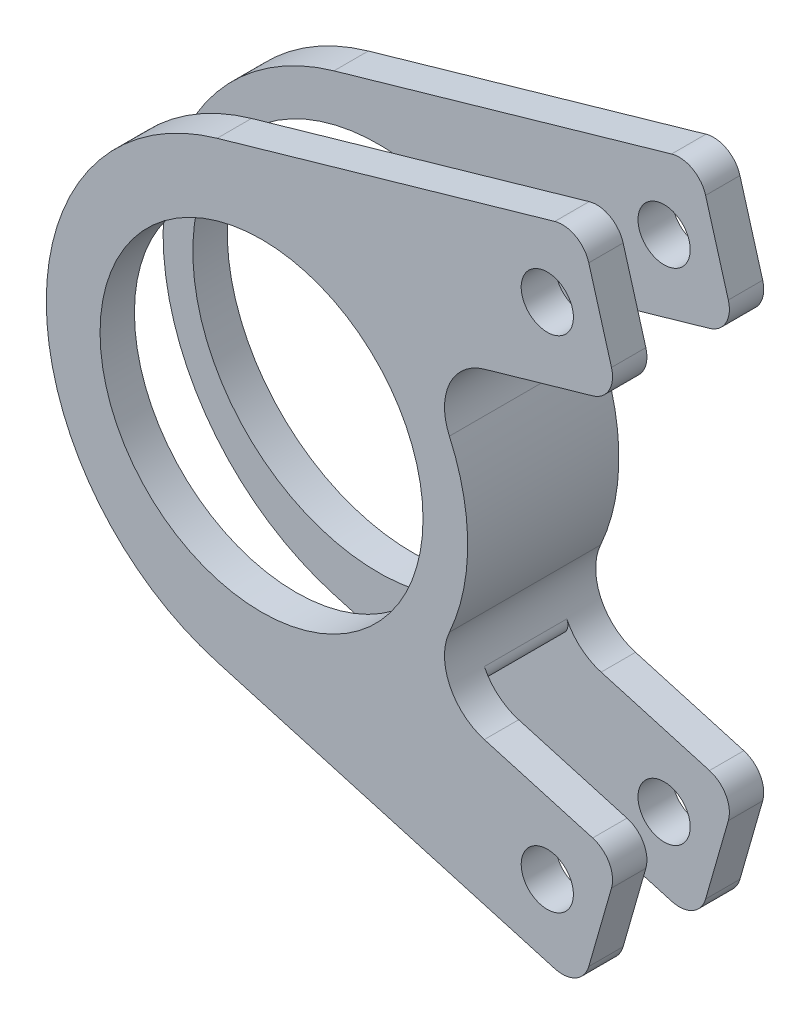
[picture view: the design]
ISO-10303-21;
HEADER;
FILE_DESCRIPTION(('STEP AP214'),'2;1');
FILE_NAME('part.step','',(''),(''),'','','');
FILE_SCHEMA(('AUTOMOTIVE_DESIGN { 1 0 10303 214 1 1 1 1 }'));
ENDSEC;
DATA;
#1=APPLICATION_CONTEXT('core data for automotive mechanical design processes');
#2=APPLICATION_PROTOCOL_DEFINITION('international standard','automotive_design',2000,#1);
#3=PRODUCT_CONTEXT('',#1,'mechanical');
#4=PRODUCT('Part','Part','',(#3));
#5=PRODUCT_RELATED_PRODUCT_CATEGORY('part','',(#4));
#6=PRODUCT_DEFINITION_FORMATION('','',#4);
#7=PRODUCT_DEFINITION_CONTEXT('part definition',#1,'design');
#8=PRODUCT_DEFINITION('design','',#6,#7);
#9=PRODUCT_DEFINITION_SHAPE('','',#8);
#10=(LENGTH_UNIT() NAMED_UNIT(*) SI_UNIT(.MILLI.,.METRE.));
#11=(NAMED_UNIT(*) PLANE_ANGLE_UNIT() SI_UNIT($,.RADIAN.));
#12=(NAMED_UNIT(*) SI_UNIT($,.STERADIAN.) SOLID_ANGLE_UNIT());
#13=UNCERTAINTY_MEASURE_WITH_UNIT(LENGTH_MEASURE(1.E-05),#10,'distance_accuracy_value','');
#14=(GEOMETRIC_REPRESENTATION_CONTEXT(3) GLOBAL_UNCERTAINTY_ASSIGNED_CONTEXT((#13)) GLOBAL_UNIT_ASSIGNED_CONTEXT((#10,
#11,#12)) REPRESENTATION_CONTEXT('',''));
#15=CARTESIAN_POINT('',(0.,0.,0.));
#16=DIRECTION('',(0.,0.,1.));
#17=DIRECTION('',(1.,0.,0.));
#18=AXIS2_PLACEMENT_3D('',#15,#16,#17);
#19=CARTESIAN_POINT('',(658.968984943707,116.70480409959,55.));
#20=DIRECTION('',(-0.275637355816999,0.961261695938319,0.));
#21=DIRECTION('',(-0.961261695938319,-0.275637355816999,0.));
#22=AXIS2_PLACEMENT_3D('',#19,#20,#21);
#23=PLANE('',#22);
#24=DIRECTION('',(0.961261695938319,0.275637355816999,0.));
#25=VECTOR('',#24,1.);
#26=CARTESIAN_POINT('',(849.712684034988,171.399679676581,-30.));
#27=LINE('',#26,#25);
#28=CARTESIAN_POINT('',(658.968984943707,116.70480409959,-30.));
#29=VERTEX_POINT('',#28);
#30=CARTESIAN_POINT('',(737.793083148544,139.307250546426,-30.));
#31=VERTEX_POINT('',#30);
#32=EDGE_CURVE('E280',#29,#31,#27,.T.);
#33=ORIENTED_EDGE('',*,*,#32,.F.);
#34=DIRECTION('',(0.,0.,-1.));
#35=VECTOR('',#34,1.);
#36=CARTESIAN_POINT('',(658.968984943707,116.70480409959,55.));
#37=LINE('',#36,#35);
#38=CARTESIAN_POINT('',(658.968984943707,116.70480409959,-55.));
#39=VERTEX_POINT('',#38);
#40=EDGE_CURVE('E491',#29,#39,#37,.T.);
#41=ORIENTED_EDGE('',*,*,#40,.T.);
#42=DIRECTION('',(0.961261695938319,0.275637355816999,0.));
#43=VECTOR('',#42,1.);
#44=CARTESIAN_POINT('',(658.968984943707,116.70480409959,-55.));
#45=LINE('',#44,#43);
#46=CARTESIAN_POINT('',(737.793083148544,139.307250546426,-55.));
#47=VERTEX_POINT('',#46);
#48=EDGE_CURVE('E417',#39,#47,#45,.T.);
#49=ORIENTED_EDGE('',*,*,#48,.T.);
#50=DIRECTION('',(0.,0.,-1.));
#51=VECTOR('',#50,1.);
#52=CARTESIAN_POINT('',(737.793083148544,139.307250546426,55.));
#53=LINE('',#52,#51);
#54=EDGE_CURVE('E487',#31,#47,#53,.T.);
#55=ORIENTED_EDGE('',*,*,#54,.F.);
#56=EDGE_LOOP('',(#33,#41,#49,#55));
#57=FACE_BOUND('',#56,.T.);
#58=ADVANCED_FACE('F34',(#57),#23,.F.);
#59=CARTESIAN_POINT('',(732.280336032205,158.532484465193,55.));
#60=DIRECTION('',(0.,0.,-1.));
#61=DIRECTION('',(-1.,0.,0.));
#62=AXIS2_PLACEMENT_3D('',#59,#60,#61);
#63=CYLINDRICAL_SURFACE('',#62,20.);
#64=CARTESIAN_POINT('',(732.280336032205,158.532484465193,-30.));
#65=DIRECTION('',(0.,0.,1.));
#66=DIRECTION('',(1.,0.,0.));
#67=AXIS2_PLACEMENT_3D('',#64,#65,#66);
#68=CIRCLE('',#67,20.);
#69=CARTESIAN_POINT('',(751.505569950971,164.045231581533,-30.));
#70=VERTEX_POINT('',#69);
#71=EDGE_CURVE('E361',#31,#70,#68,.T.);
#72=ORIENTED_EDGE('',*,*,#71,.F.);
#73=ORIENTED_EDGE('',*,*,#54,.T.);
#74=CARTESIAN_POINT('',(732.280336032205,158.532484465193,-55.));
#75=DIRECTION('',(0.,0.,1.));
#76=DIRECTION('',(1.,0.,0.));
#77=AXIS2_PLACEMENT_3D('',#74,#75,#76);
#78=CIRCLE('',#77,20.);
#79=CARTESIAN_POINT('',(751.505569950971,164.045231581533,-55.));
#80=VERTEX_POINT('',#79);
#81=EDGE_CURVE('E420',#47,#80,#78,.T.);
#82=ORIENTED_EDGE('',*,*,#81,.T.);
#83=DIRECTION('',(0.,0.,-1.));
#84=VECTOR('',#83,1.);
#85=CARTESIAN_POINT('',(751.505569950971,164.045231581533,55.));
#86=LINE('',#85,#84);
#87=EDGE_CURVE('E483',#70,#80,#86,.T.);
#88=ORIENTED_EDGE('',*,*,#87,.F.);
#89=EDGE_LOOP('',(#72,#73,#82,#88));
#90=FACE_BOUND('',#89,.T.);
#91=ADVANCED_FACE('F611',(#90),#63,.T.);
#92=CARTESIAN_POINT('',(751.505569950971,164.045231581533,55.));
#93=DIRECTION('',(-0.961261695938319,-0.275637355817,0.));
#94=DIRECTION('',(0.275637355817,-0.961261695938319,0.));
#95=AXIS2_PLACEMENT_3D('',#92,#93,#94);
#96=PLANE('',#95);
#97=DIRECTION('',(-0.275637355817,0.961261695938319,0.));
#98=VECTOR('',#97,1.);
#99=CARTESIAN_POINT('',(751.505569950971,164.045231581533,-30.));
#100=LINE('',#99,#98);
#101=CARTESIAN_POINT('',(734.967328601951,221.720933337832,-30.));
#102=VERTEX_POINT('',#101);
#103=EDGE_CURVE('E359',#70,#102,#100,.T.);
#104=ORIENTED_EDGE('',*,*,#103,.F.);
#105=ORIENTED_EDGE('',*,*,#87,.T.);
#106=DIRECTION('',(-0.275637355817,0.961261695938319,0.));
#107=VECTOR('',#106,1.);
#108=CARTESIAN_POINT('',(751.505569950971,164.045231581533,-55.));
#109=LINE('',#108,#107);
#110=CARTESIAN_POINT('',(734.967328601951,221.720933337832,-55.));
#111=VERTEX_POINT('',#110);
#112=EDGE_CURVE('E423',#80,#111,#109,.T.);
#113=ORIENTED_EDGE('',*,*,#112,.T.);
#114=DIRECTION('',(0.,0.,-1.));
#115=VECTOR('',#114,1.);
#116=CARTESIAN_POINT('',(734.967328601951,221.720933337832,55.));
#117=LINE('',#116,#115);
#118=EDGE_CURVE('E479',#102,#111,#117,.T.);
#119=ORIENTED_EDGE('',*,*,#118,.F.);
#120=EDGE_LOOP('',(#104,#105,#113,#119));
#121=FACE_BOUND('',#120,.T.);
#122=ADVANCED_FACE('F617',(#121),#96,.F.);
#123=CARTESIAN_POINT('',(715.742094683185,216.208186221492,55.));
#124=DIRECTION('',(0.,0.,-1.));
#125=DIRECTION('',(-1.,0.,0.));
#126=AXIS2_PLACEMENT_3D('',#123,#124,#125);
#127=CYLINDRICAL_SURFACE('',#126,20.);
#128=CARTESIAN_POINT('',(715.742094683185,216.208186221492,-30.));
#129=DIRECTION('',(0.,0.,1.));
#130=DIRECTION('',(1.,0.,0.));
#131=AXIS2_PLACEMENT_3D('',#128,#129,#130);
#132=CIRCLE('',#131,20.);
#133=CARTESIAN_POINT('',(710.229347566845,235.433420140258,-30.));
#134=VERTEX_POINT('',#133);
#135=EDGE_CURVE('E357',#102,#134,#132,.T.);
#136=ORIENTED_EDGE('',*,*,#135,.F.);
#137=ORIENTED_EDGE('',*,*,#118,.T.);
#138=CARTESIAN_POINT('',(715.742094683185,216.208186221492,-55.));
#139=DIRECTION('',(0.,0.,1.));
#140=DIRECTION('',(1.,0.,0.));
#141=AXIS2_PLACEMENT_3D('',#138,#139,#140);
#142=CIRCLE('',#141,20.);
#143=CARTESIAN_POINT('',(710.229347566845,235.433420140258,-55.));
#144=VERTEX_POINT('',#143);
#145=EDGE_CURVE('E426',#111,#144,#142,.T.);
#146=ORIENTED_EDGE('',*,*,#145,.T.);
#147=DIRECTION('',(0.,0.,-1.));
#148=VECTOR('',#147,1.);
#149=CARTESIAN_POINT('',(710.229347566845,235.433420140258,55.));
#150=LINE('',#149,#148);
#151=EDGE_CURVE('E475',#134,#144,#150,.T.);
#152=ORIENTED_EDGE('',*,*,#151,.F.);
#153=EDGE_LOOP('',(#136,#137,#146,#152));
#154=FACE_BOUND('',#153,.T.);
#155=ADVANCED_FACE('F676',(#154),#127,.T.);
#156=CARTESIAN_POINT('',(464.549050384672,164.985728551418,55.));
#157=DIRECTION('',(0.275637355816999,-0.961261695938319,0.));
#158=DIRECTION('',(0.961261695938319,0.275637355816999,0.));
#159=AXIS2_PLACEMENT_3D('',#156,#157,#158);
#160=PLANE('',#159);
#161=DIRECTION('',(-0.961261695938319,-0.275637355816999,0.));
#162=VECTOR('',#161,1.);
#163=CARTESIAN_POINT('',(464.549050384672,164.985728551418,-30.));
#164=LINE('',#163,#162);
#165=CARTESIAN_POINT('',(464.549050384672,164.985728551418,-30.));
#166=VERTEX_POINT('',#165);
#167=EDGE_CURVE('E355',#134,#166,#164,.T.);
#168=ORIENTED_EDGE('',*,*,#167,.F.);
#169=ORIENTED_EDGE('',*,*,#151,.T.);
#170=DIRECTION('',(-0.961261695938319,-0.275637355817,0.));
#171=VECTOR('',#170,1.);
#172=CARTESIAN_POINT('',(464.549050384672,164.985728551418,-55.));
#173=LINE('',#172,#171);
#174=CARTESIAN_POINT('',(464.549050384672,164.985728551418,-55.));
#175=VERTEX_POINT('',#174);
#176=EDGE_CURVE('E429',#144,#175,#173,.T.);
#177=ORIENTED_EDGE('',*,*,#176,.T.);
#178=DIRECTION('',(0.,0.,-1.));
#179=VECTOR('',#178,1.);
#180=CARTESIAN_POINT('',(464.549050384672,164.985728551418,55.));
#181=LINE('',#180,#179);
#182=EDGE_CURVE('E471',#166,#175,#181,.T.);
#183=ORIENTED_EDGE('',*,*,#182,.F.);
#184=EDGE_LOOP('',(#168,#169,#177,#183));
#185=FACE_BOUND('',#184,.T.);
#186=ADVANCED_FACE('F673',(#185),#160,.F.);
#187=CARTESIAN_POINT('',(511.857946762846,0.,55.));
#188=DIRECTION('',(0.,0.,-1.));
#189=DIRECTION('',(-1.,0.,0.));
#190=AXIS2_PLACEMENT_3D('',#187,#188,#189);
#191=CYLINDRICAL_SURFACE('',#190,171.634560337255);
#192=CARTESIAN_POINT('',(511.857946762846,0.,-30.));
#193=DIRECTION('',(0.,0.,1.));
#194=DIRECTION('',(1.,0.,0.));
#195=AXIS2_PLACEMENT_3D('',#192,#193,#194);
#196=CIRCLE('',#195,171.634560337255);
#197=CARTESIAN_POINT('',(464.549050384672,-164.985728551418,-30.));
#198=VERTEX_POINT('',#197);
#199=EDGE_CURVE('E353',#166,#198,#196,.T.);
#200=ORIENTED_EDGE('',*,*,#199,.F.);
#201=ORIENTED_EDGE('',*,*,#182,.T.);
#202=CARTESIAN_POINT('',(511.857946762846,0.,-55.));
#203=DIRECTION('',(0.,0.,1.));
#204=DIRECTION('',(1.,0.,0.));
#205=AXIS2_PLACEMENT_3D('',#202,#203,#204);
#206=CIRCLE('',#205,171.634560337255);
#207=CARTESIAN_POINT('',(464.549050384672,-164.985728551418,-55.));
#208=VERTEX_POINT('',#207);
#209=EDGE_CURVE('E432',#175,#208,#206,.T.);
#210=ORIENTED_EDGE('',*,*,#209,.T.);
#211=DIRECTION('',(0.,0.,-1.));
#212=VECTOR('',#211,1.);
#213=CARTESIAN_POINT('',(464.549050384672,-164.985728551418,55.));
#214=LINE('',#213,#212);
#215=EDGE_CURVE('E467',#198,#208,#214,.T.);
#216=ORIENTED_EDGE('',*,*,#215,.F.);
#217=EDGE_LOOP('',(#200,#201,#210,#216));
#218=FACE_BOUND('',#217,.T.);
#219=ADVANCED_FACE('F670',(#218),#191,.T.);
#220=CARTESIAN_POINT('',(464.549050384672,-164.985728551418,55.));
#221=DIRECTION('',(0.275637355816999,0.961261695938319,0.));
#222=DIRECTION('',(-0.961261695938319,0.275637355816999,0.));
#223=AXIS2_PLACEMENT_3D('',#220,#221,#222);
#224=PLANE('',#223);
#225=DIRECTION('',(0.961261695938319,-0.275637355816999,0.));
#226=VECTOR('',#225,1.);
#227=CARTESIAN_POINT('',(464.549050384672,-164.985728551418,-30.));
#228=LINE('',#227,#226);
#229=CARTESIAN_POINT('',(710.229347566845,-235.433420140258,-30.));
#230=VERTEX_POINT('',#229);
#231=EDGE_CURVE('E351',#198,#230,#228,.T.);
#232=ORIENTED_EDGE('',*,*,#231,.F.);
#233=ORIENTED_EDGE('',*,*,#215,.T.);
#234=DIRECTION('',(0.961261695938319,-0.275637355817,0.));
#235=VECTOR('',#234,1.);
#236=CARTESIAN_POINT('',(464.549050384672,-164.985728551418,-55.));
#237=LINE('',#236,#235);
#238=CARTESIAN_POINT('',(710.229347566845,-235.433420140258,-55.));
#239=VERTEX_POINT('',#238);
#240=EDGE_CURVE('E435',#208,#239,#237,.T.);
#241=ORIENTED_EDGE('',*,*,#240,.T.);
#242=DIRECTION('',(0.,0.,-1.));
#243=VECTOR('',#242,1.);
#244=CARTESIAN_POINT('',(710.229347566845,-235.433420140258,55.));
#245=LINE('',#244,#243);
#246=EDGE_CURVE('E463',#230,#239,#245,.T.);
#247=ORIENTED_EDGE('',*,*,#246,.F.);
#248=EDGE_LOOP('',(#232,#233,#241,#247));
#249=FACE_BOUND('',#248,.T.);
#250=ADVANCED_FACE('F667',(#249),#224,.F.);
#251=CARTESIAN_POINT('',(715.742094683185,-216.208186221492,55.));
#252=DIRECTION('',(0.,0.,-1.));
#253=DIRECTION('',(-1.,0.,0.));
#254=AXIS2_PLACEMENT_3D('',#251,#252,#253);
#255=CYLINDRICAL_SURFACE('',#254,20.);
#256=CARTESIAN_POINT('',(715.742094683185,-216.208186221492,-30.));
#257=DIRECTION('',(0.,0.,1.));
#258=DIRECTION('',(1.,0.,0.));
#259=AXIS2_PLACEMENT_3D('',#256,#257,#258);
#260=CIRCLE('',#259,20.);
#261=CARTESIAN_POINT('',(734.967328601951,-221.720933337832,-30.));
#262=VERTEX_POINT('',#261);
#263=EDGE_CURVE('E349',#230,#262,#260,.T.);
#264=ORIENTED_EDGE('',*,*,#263,.F.);
#265=ORIENTED_EDGE('',*,*,#246,.T.);
#266=CARTESIAN_POINT('',(715.742094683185,-216.208186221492,-55.));
#267=DIRECTION('',(0.,0.,1.));
#268=DIRECTION('',(-1.,0.,0.));
#269=AXIS2_PLACEMENT_3D('',#266,#267,#268);
#270=CIRCLE('',#269,20.);
#271=CARTESIAN_POINT('',(734.967328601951,-221.720933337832,-55.));
#272=VERTEX_POINT('',#271);
#273=EDGE_CURVE('E438',#239,#272,#270,.T.);
#274=ORIENTED_EDGE('',*,*,#273,.T.);
#275=DIRECTION('',(0.,0.,-1.));
#276=VECTOR('',#275,1.);
#277=CARTESIAN_POINT('',(734.967328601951,-221.720933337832,55.));
#278=LINE('',#277,#276);
#279=EDGE_CURVE('E459',#262,#272,#278,.T.);
#280=ORIENTED_EDGE('',*,*,#279,.F.);
#281=EDGE_LOOP('',(#264,#265,#274,#280));
#282=FACE_BOUND('',#281,.T.);
#283=ADVANCED_FACE('F664',(#282),#255,.T.);
#284=CARTESIAN_POINT('',(751.505569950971,-164.045231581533,55.));
#285=DIRECTION('',(-0.961261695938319,0.275637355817,0.));
#286=DIRECTION('',(-0.275637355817,-0.961261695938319,0.));
#287=AXIS2_PLACEMENT_3D('',#284,#285,#286);
#288=PLANE('',#287);
#289=DIRECTION('',(0.275637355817,0.961261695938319,0.));
#290=VECTOR('',#289,1.);
#291=CARTESIAN_POINT('',(751.505569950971,-164.045231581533,-30.));
#292=LINE('',#291,#290);
#293=CARTESIAN_POINT('',(751.505569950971,-164.045231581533,-30.));
#294=VERTEX_POINT('',#293);
#295=EDGE_CURVE('E347',#262,#294,#292,.T.);
#296=ORIENTED_EDGE('',*,*,#295,.F.);
#297=ORIENTED_EDGE('',*,*,#279,.T.);
#298=DIRECTION('',(0.275637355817,0.961261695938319,0.));
#299=VECTOR('',#298,1.);
#300=CARTESIAN_POINT('',(751.505569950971,-164.045231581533,-55.));
#301=LINE('',#300,#299);
#302=CARTESIAN_POINT('',(751.505569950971,-164.045231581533,-55.));
#303=VERTEX_POINT('',#302);
#304=EDGE_CURVE('E441',#272,#303,#301,.T.);
#305=ORIENTED_EDGE('',*,*,#304,.T.);
#306=DIRECTION('',(0.,0.,-1.));
#307=VECTOR('',#306,1.);
#308=CARTESIAN_POINT('',(751.505569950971,-164.045231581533,55.));
#309=LINE('',#308,#307);
#310=EDGE_CURVE('E455',#294,#303,#309,.T.);
#311=ORIENTED_EDGE('',*,*,#310,.F.);
#312=EDGE_LOOP('',(#296,#297,#305,#311));
#313=FACE_BOUND('',#312,.T.);
#314=ADVANCED_FACE('F661',(#313),#288,.F.);
#315=CARTESIAN_POINT('',(732.280336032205,-158.532484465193,55.));
#316=DIRECTION('',(0.,0.,-1.));
#317=DIRECTION('',(-1.,0.,0.));
#318=AXIS2_PLACEMENT_3D('',#315,#316,#317);
#319=CYLINDRICAL_SURFACE('',#318,20.);
#320=CARTESIAN_POINT('',(732.280336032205,-158.532484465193,-30.));
#321=DIRECTION('',(0.,0.,1.));
#322=DIRECTION('',(1.,0.,0.));
#323=AXIS2_PLACEMENT_3D('',#320,#321,#322);
#324=CIRCLE('',#323,20.);
#325=CARTESIAN_POINT('',(737.793083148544,-139.307250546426,-30.));
#326=VERTEX_POINT('',#325);
#327=EDGE_CURVE('E345',#294,#326,#324,.T.);
#328=ORIENTED_EDGE('',*,*,#327,.F.);
#329=ORIENTED_EDGE('',*,*,#310,.T.);
#330=CARTESIAN_POINT('',(732.280336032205,-158.532484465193,-55.));
#331=DIRECTION('',(0.,0.,1.));
#332=DIRECTION('',(-1.,0.,0.));
#333=AXIS2_PLACEMENT_3D('',#330,#331,#332);
#334=CIRCLE('',#333,20.);
#335=CARTESIAN_POINT('',(737.793083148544,-139.307250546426,-55.));
#336=VERTEX_POINT('',#335);
#337=EDGE_CURVE('E444',#303,#336,#334,.T.);
#338=ORIENTED_EDGE('',*,*,#337,.T.);
#339=DIRECTION('',(0.,0.,-1.));
#340=VECTOR('',#339,1.);
#341=CARTESIAN_POINT('',(737.793083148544,-139.307250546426,55.));
#342=LINE('',#341,#340);
#343=EDGE_CURVE('E451',#326,#336,#342,.T.);
#344=ORIENTED_EDGE('',*,*,#343,.F.);
#345=EDGE_LOOP('',(#328,#329,#338,#344));
#346=FACE_BOUND('',#345,.T.);
#347=ADVANCED_FACE('F658',(#346),#319,.T.);
#348=CARTESIAN_POINT('',(658.968984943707,-116.70480409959,55.));
#349=DIRECTION('',(-0.275637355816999,-0.961261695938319,0.));
#350=DIRECTION('',(0.961261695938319,-0.275637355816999,0.));
#351=AXIS2_PLACEMENT_3D('',#348,#349,#350);
#352=PLANE('',#351);
#353=DIRECTION('',(-0.961261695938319,0.275637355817,0.));
#354=VECTOR('',#353,1.);
#355=CARTESIAN_POINT('',(860.229370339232,-174.415290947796,-30.));
#356=LINE('',#355,#354);
#357=CARTESIAN_POINT('',(658.968984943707,-116.70480409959,-30.));
#358=VERTEX_POINT('',#357);
#359=EDGE_CURVE('E284',#326,#358,#356,.T.);
#360=ORIENTED_EDGE('',*,*,#359,.F.);
#361=ORIENTED_EDGE('',*,*,#343,.T.);
#362=DIRECTION('',(-0.961261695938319,0.275637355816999,0.));
#363=VECTOR('',#362,1.);
#364=CARTESIAN_POINT('',(658.968984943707,-116.70480409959,-55.));
#365=LINE('',#364,#363);
#366=CARTESIAN_POINT('',(658.968984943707,-116.70480409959,-55.));
#367=VERTEX_POINT('',#366);
#368=EDGE_CURVE('E383',#336,#367,#365,.T.);
#369=ORIENTED_EDGE('',*,*,#368,.T.);
#370=DIRECTION('',(0.,0.,-1.));
#371=VECTOR('',#370,1.);
#372=CARTESIAN_POINT('',(658.968984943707,-116.70480409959,55.));
#373=LINE('',#372,#371);
#374=EDGE_CURVE('E409',#358,#367,#373,.T.);
#375=ORIENTED_EDGE('',*,*,#374,.F.);
#376=EDGE_LOOP('',(#360,#361,#369,#375));
#377=FACE_BOUND('',#376,.T.);
#378=ADVANCED_FACE('F655',(#377),#352,.F.);
#379=CARTESIAN_POINT('',(704.785981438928,181.857588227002,55.));
#380=DIRECTION('',(0.,0.,-1.));
#381=DIRECTION('',(-1.,0.,0.));
#382=AXIS2_PLACEMENT_3D('',#379,#380,#381);
#383=CYLINDRICAL_SURFACE('',#382,19.);
#384=CARTESIAN_POINT('',(704.785981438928,181.857588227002,-55.));
#385=DIRECTION('',(0.,0.,1.));
#386=DIRECTION('',(1.,0.,0.));
#387=AXIS2_PLACEMENT_3D('',#384,#385,#386);
#388=CIRCLE('',#387,19.);
#389=CARTESIAN_POINT('',(723.785981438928,181.857588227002,-55.));
#390=VERTEX_POINT('',#389);
#391=EDGE_CURVE('E367',#390,#390,#388,.T.);
#392=ORIENTED_EDGE('',*,*,#391,.F.);
#393=EDGE_LOOP('',(#392));
#394=FACE_BOUND('',#393,.T.);
#395=CARTESIAN_POINT('',(704.785981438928,181.857588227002,-30.));
#396=DIRECTION('',(0.,0.,1.));
#397=DIRECTION('',(1.,0.,0.));
#398=AXIS2_PLACEMENT_3D('',#395,#396,#397);
#399=CIRCLE('',#398,19.);
#400=CARTESIAN_POINT('',(723.785981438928,181.857588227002,-30.));
#401=VERTEX_POINT('',#400);
#402=EDGE_CURVE('E342',#401,#401,#399,.T.);
#403=ORIENTED_EDGE('',*,*,#402,.T.);
#404=EDGE_LOOP('',(#403));
#405=FACE_BOUND('',#404,.T.);
#406=ADVANCED_FACE('F751',(#394,#405),#383,.F.);
#407=CARTESIAN_POINT('',(704.785981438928,-181.857588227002,55.));
#408=DIRECTION('',(0.,0.,-1.));
#409=DIRECTION('',(-1.,0.,0.));
#410=AXIS2_PLACEMENT_3D('',#407,#408,#409);
#411=CYLINDRICAL_SURFACE('',#410,19.);
#412=CARTESIAN_POINT('',(704.785981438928,-181.857588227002,-55.));
#413=DIRECTION('',(0.,0.,1.));
#414=DIRECTION('',(-1.,0.,0.));
#415=AXIS2_PLACEMENT_3D('',#412,#413,#414);
#416=CIRCLE('',#415,19.);
#417=CARTESIAN_POINT('',(685.785981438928,-181.857588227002,-55.));
#418=VERTEX_POINT('',#417);
#419=EDGE_CURVE('E363',#418,#418,#416,.T.);
#420=ORIENTED_EDGE('',*,*,#419,.F.);
#421=EDGE_LOOP('',(#420));
#422=FACE_BOUND('',#421,.T.);
#423=CARTESIAN_POINT('',(704.785981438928,-181.857588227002,-30.));
#424=DIRECTION('',(0.,0.,1.));
#425=DIRECTION('',(1.,0.,0.));
#426=AXIS2_PLACEMENT_3D('',#423,#424,#425);
#427=CIRCLE('',#426,19.);
#428=CARTESIAN_POINT('',(723.785981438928,-181.857588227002,-30.));
#429=VERTEX_POINT('',#428);
#430=EDGE_CURVE('E341',#429,#429,#427,.T.);
#431=ORIENTED_EDGE('',*,*,#430,.T.);
#432=EDGE_LOOP('',(#431));
#433=FACE_BOUND('',#432,.T.);
#434=ADVANCED_FACE('F645',(#422,#433),#411,.F.);
#435=CARTESIAN_POINT('',(669.994479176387,-78.2543362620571,55.));
#436=DIRECTION('',(0.,0.,-1.));
#437=DIRECTION('',(-1.,0.,0.));
#438=AXIS2_PLACEMENT_3D('',#435,#436,#437);
#439=PLANE('',#438);
#440=CARTESIAN_POINT('',(704.785981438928,181.857588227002,55.));
#441=DIRECTION('',(0.,0.,1.));
#442=DIRECTION('',(1.,0.,0.));
#443=AXIS2_PLACEMENT_3D('',#440,#441,#442);
#444=CIRCLE('',#443,19.);
#445=CARTESIAN_POINT('',(723.785981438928,181.857588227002,55.));
#446=VERTEX_POINT('',#445);
#447=EDGE_CURVE('E370',#446,#446,#444,.T.);
#448=ORIENTED_EDGE('',*,*,#447,.F.);
#449=EDGE_LOOP('',(#448));
#450=FACE_BOUND('',#449,.T.);
#451=CARTESIAN_POINT('',(669.994479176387,-78.2543362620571,55.));
#452=DIRECTION('',(0.,0.,-1.));
#453=DIRECTION('',(-1.,0.,0.));
#454=AXIS2_PLACEMENT_3D('',#451,#452,#453);
#455=CIRCLE('',#454,40.);
#456=CARTESIAN_POINT('',(658.968984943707,-116.70480409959,55.));
#457=VERTEX_POINT('',#456);
#458=CARTESIAN_POINT('',(633.544682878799,-61.7797391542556,55.));
#459=VERTEX_POINT('',#458);
#460=EDGE_CURVE('E379',#457,#459,#455,.T.);
#461=ORIENTED_EDGE('',*,*,#460,.T.);
#462=CARTESIAN_POINT('',(496.857946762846,0.,55.));
#463=DIRECTION('',(0.,0.,1.));
#464=DIRECTION('',(1.,0.,0.));
#465=AXIS2_PLACEMENT_3D('',#462,#463,#464);
#466=CIRCLE('',#465,150.);
#467=CARTESIAN_POINT('',(633.544682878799,61.7797391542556,55.));
#468=VERTEX_POINT('',#467);
#469=EDGE_CURVE('E382',#459,#468,#466,.T.);
#470=ORIENTED_EDGE('',*,*,#469,.T.);
#471=CARTESIAN_POINT('',(669.994479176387,78.2543362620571,55.));
#472=DIRECTION('',(0.,0.,-1.));
#473=DIRECTION('',(1.,0.,0.));
#474=AXIS2_PLACEMENT_3D('',#471,#472,#473);
#475=CIRCLE('',#474,40.);
#476=CARTESIAN_POINT('',(658.968984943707,116.70480409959,55.));
#477=VERTEX_POINT('',#476);
#478=EDGE_CURVE('E385',#468,#477,#475,.T.);
#479=ORIENTED_EDGE('',*,*,#478,.T.);
#480=DIRECTION('',(0.961261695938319,0.275637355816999,0.));
#481=VECTOR('',#480,1.);
#482=CARTESIAN_POINT('',(658.968984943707,116.70480409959,55.));
#483=LINE('',#482,#481);
#484=CARTESIAN_POINT('',(737.793083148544,139.307250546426,55.));
#485=VERTEX_POINT('',#484);
#486=EDGE_CURVE('E387',#477,#485,#483,.T.);
#487=ORIENTED_EDGE('',*,*,#486,.T.);
#488=CARTESIAN_POINT('',(732.280336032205,158.532484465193,55.));
#489=DIRECTION('',(0.,0.,1.));
#490=DIRECTION('',(1.,0.,0.));
#491=AXIS2_PLACEMENT_3D('',#488,#489,#490);
#492=CIRCLE('',#491,20.);
#493=CARTESIAN_POINT('',(751.505569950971,164.045231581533,55.));
#494=VERTEX_POINT('',#493);
#495=EDGE_CURVE('E389',#485,#494,#492,.T.);
#496=ORIENTED_EDGE('',*,*,#495,.T.);
#497=DIRECTION('',(-0.275637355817,0.961261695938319,0.));
#498=VECTOR('',#497,1.);
#499=CARTESIAN_POINT('',(751.505569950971,164.045231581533,55.));
#500=LINE('',#499,#498);
#501=CARTESIAN_POINT('',(734.967328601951,221.720933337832,55.));
#502=VERTEX_POINT('',#501);
#503=EDGE_CURVE('E391',#494,#502,#500,.T.);
#504=ORIENTED_EDGE('',*,*,#503,.T.);
#505=CARTESIAN_POINT('',(715.742094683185,216.208186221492,55.));
#506=DIRECTION('',(0.,0.,1.));
#507=DIRECTION('',(1.,0.,0.));
#508=AXIS2_PLACEMENT_3D('',#505,#506,#507);
#509=CIRCLE('',#508,20.);
#510=CARTESIAN_POINT('',(710.229347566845,235.433420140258,55.));
#511=VERTEX_POINT('',#510);
#512=EDGE_CURVE('E393',#502,#511,#509,.T.);
#513=ORIENTED_EDGE('',*,*,#512,.T.);
#514=DIRECTION('',(-0.961261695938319,-0.275637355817,0.));
#515=VECTOR('',#514,1.);
#516=CARTESIAN_POINT('',(464.549050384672,164.985728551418,55.));
#517=LINE('',#516,#515);
#518=CARTESIAN_POINT('',(464.549050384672,164.985728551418,55.));
#519=VERTEX_POINT('',#518);
#520=EDGE_CURVE('E395',#511,#519,#517,.T.);
#521=ORIENTED_EDGE('',*,*,#520,.T.);
#522=CARTESIAN_POINT('',(511.857946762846,0.,55.));
#523=DIRECTION('',(0.,0.,1.));
#524=DIRECTION('',(1.,0.,0.));
#525=AXIS2_PLACEMENT_3D('',#522,#523,#524);
#526=CIRCLE('',#525,171.634560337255);
#527=CARTESIAN_POINT('',(464.549050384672,-164.985728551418,55.));
#528=VERTEX_POINT('',#527);
#529=EDGE_CURVE('E397',#519,#528,#526,.T.);
#530=ORIENTED_EDGE('',*,*,#529,.T.);
#531=DIRECTION('',(0.961261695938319,-0.275637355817,0.));
#532=VECTOR('',#531,1.);
#533=CARTESIAN_POINT('',(464.549050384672,-164.985728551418,55.));
#534=LINE('',#533,#532);
#535=CARTESIAN_POINT('',(710.229347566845,-235.433420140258,55.));
#536=VERTEX_POINT('',#535);
#537=EDGE_CURVE('E399',#528,#536,#534,.T.);
#538=ORIENTED_EDGE('',*,*,#537,.T.);
#539=CARTESIAN_POINT('',(715.742094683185,-216.208186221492,55.));
#540=DIRECTION('',(0.,0.,1.));
#541=DIRECTION('',(-1.,0.,0.));
#542=AXIS2_PLACEMENT_3D('',#539,#540,#541);
#543=CIRCLE('',#542,20.);
#544=CARTESIAN_POINT('',(734.967328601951,-221.720933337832,55.));
#545=VERTEX_POINT('',#544);
#546=EDGE_CURVE('E401',#536,#545,#543,.T.);
#547=ORIENTED_EDGE('',*,*,#546,.T.);
#548=DIRECTION('',(0.275637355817,0.961261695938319,0.));
#549=VECTOR('',#548,1.);
#550=CARTESIAN_POINT('',(751.505569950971,-164.045231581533,55.));
#551=LINE('',#550,#549);
#552=CARTESIAN_POINT('',(751.505569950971,-164.045231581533,55.));
#553=VERTEX_POINT('',#552);
#554=EDGE_CURVE('E403',#545,#553,#551,.T.);
#555=ORIENTED_EDGE('',*,*,#554,.T.);
#556=CARTESIAN_POINT('',(732.280336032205,-158.532484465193,55.));
#557=DIRECTION('',(0.,0.,1.));
#558=DIRECTION('',(-1.,0.,0.));
#559=AXIS2_PLACEMENT_3D('',#556,#557,#558);
#560=CIRCLE('',#559,20.);
#561=CARTESIAN_POINT('',(737.793083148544,-139.307250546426,55.));
#562=VERTEX_POINT('',#561);
#563=EDGE_CURVE('E405',#553,#562,#560,.T.);
#564=ORIENTED_EDGE('',*,*,#563,.T.);
#565=DIRECTION('',(-0.961261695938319,0.275637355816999,0.));
#566=VECTOR('',#565,1.);
#567=CARTESIAN_POINT('',(658.968984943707,-116.70480409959,55.));
#568=LINE('',#567,#566);
#569=EDGE_CURVE('E407',#562,#457,#568,.T.);
#570=ORIENTED_EDGE('',*,*,#569,.T.);
#571=EDGE_LOOP('',(#461,#470,#479,#487,#496,#504,#513,#521,#530,#538,#547,#555,#564,#570));
#572=FACE_BOUND('',#571,.T.);
#573=CARTESIAN_POINT('',(496.857946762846,0.,55.));
#574=DIRECTION('',(0.,0.,1.));
#575=DIRECTION('',(1.,0.,0.));
#576=AXIS2_PLACEMENT_3D('',#573,#574,#575);
#577=CIRCLE('',#576,117.5);
#578=CARTESIAN_POINT('',(614.357946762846,0.,55.));
#579=VERTEX_POINT('',#578);
#580=EDGE_CURVE('E373',#579,#579,#577,.T.);
#581=ORIENTED_EDGE('',*,*,#580,.F.);
#582=EDGE_LOOP('',(#581));
#583=FACE_BOUND('',#582,.T.);
#584=CARTESIAN_POINT('',(704.785981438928,-181.857588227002,55.));
#585=DIRECTION('',(0.,0.,1.));
#586=DIRECTION('',(-1.,0.,0.));
#587=AXIS2_PLACEMENT_3D('',#584,#585,#586);
#588=CIRCLE('',#587,19.);
#589=CARTESIAN_POINT('',(685.785981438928,-181.857588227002,55.));
#590=VERTEX_POINT('',#589);
#591=EDGE_CURVE('E364',#590,#590,#588,.T.);
#592=ORIENTED_EDGE('',*,*,#591,.F.);
#593=EDGE_LOOP('',(#592));
#594=FACE_BOUND('',#593,.T.);
#595=ADVANCED_FACE('F639',(#450,#572,#583,#594),#439,.F.);
#596=CARTESIAN_POINT('',(669.994479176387,-78.2543362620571,-55.));
#597=DIRECTION('',(0.,0.,-1.));
#598=DIRECTION('',(-1.,0.,0.));
#599=AXIS2_PLACEMENT_3D('',#596,#597,#598);
#600=PLANE('',#599);
#601=CARTESIAN_POINT('',(496.857946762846,0.,-55.));
#602=DIRECTION('',(0.,0.,1.));
#603=DIRECTION('',(1.,0.,0.));
#604=AXIS2_PLACEMENT_3D('',#601,#602,#603);
#605=CIRCLE('',#604,135.);
#606=CARTESIAN_POINT('',(631.857946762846,0.,-55.));
#607=VERTEX_POINT('',#606);
#608=EDGE_CURVE('E265',#607,#607,#605,.T.);
#609=ORIENTED_EDGE('',*,*,#608,.T.);
#610=EDGE_LOOP('',(#609));
#611=FACE_BOUND('',#610,.T.);
#612=ORIENTED_EDGE('',*,*,#391,.T.);
#613=EDGE_LOOP('',(#612));
#614=FACE_BOUND('',#613,.T.);
#615=CARTESIAN_POINT('',(669.994479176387,-78.2543362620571,-55.));
#616=DIRECTION('',(0.,0.,-1.));
#617=DIRECTION('',(-1.,0.,0.));
#618=AXIS2_PLACEMENT_3D('',#615,#616,#617);
#619=CIRCLE('',#618,40.);
#620=CARTESIAN_POINT('',(633.544682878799,-61.7797391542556,-55.));
#621=VERTEX_POINT('',#620);
#622=EDGE_CURVE('E378',#367,#621,#619,.T.);
#623=ORIENTED_EDGE('',*,*,#622,.F.);
#624=ORIENTED_EDGE('',*,*,#368,.F.);
#625=ORIENTED_EDGE('',*,*,#337,.F.);
#626=ORIENTED_EDGE('',*,*,#304,.F.);
#627=ORIENTED_EDGE('',*,*,#273,.F.);
#628=ORIENTED_EDGE('',*,*,#240,.F.);
#629=ORIENTED_EDGE('',*,*,#209,.F.);
#630=ORIENTED_EDGE('',*,*,#176,.F.);
#631=ORIENTED_EDGE('',*,*,#145,.F.);
#632=ORIENTED_EDGE('',*,*,#112,.F.);
#633=ORIENTED_EDGE('',*,*,#81,.F.);
#634=ORIENTED_EDGE('',*,*,#48,.F.);
#635=CARTESIAN_POINT('',(669.994479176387,78.2543362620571,-55.));
#636=DIRECTION('',(0.,0.,-1.));
#637=DIRECTION('',(1.,0.,0.));
#638=AXIS2_PLACEMENT_3D('',#635,#636,#637);
#639=CIRCLE('',#638,40.);
#640=CARTESIAN_POINT('',(633.544682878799,61.7797391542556,-55.));
#641=VERTEX_POINT('',#640);
#642=EDGE_CURVE('E414',#641,#39,#639,.T.);
#643=ORIENTED_EDGE('',*,*,#642,.F.);
#644=CARTESIAN_POINT('',(496.857946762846,0.,-55.));
#645=DIRECTION('',(0.,0.,1.));
#646=DIRECTION('',(1.,0.,0.));
#647=AXIS2_PLACEMENT_3D('',#644,#645,#646);
#648=CIRCLE('',#647,150.);
#649=EDGE_CURVE('E412',#621,#641,#648,.T.);
#650=ORIENTED_EDGE('',*,*,#649,.F.);
#651=EDGE_LOOP('',(#623,#624,#625,#626,#627,#628,#629,#630,#631,#632,#633,#634,#643,#650));
#652=FACE_BOUND('',#651,.T.);
#653=ORIENTED_EDGE('',*,*,#419,.T.);
#654=EDGE_LOOP('',(#653));
#655=FACE_BOUND('',#654,.T.);
#656=ADVANCED_FACE('F635',(#611,#614,#652,#655),#600,.T.);
#657=CARTESIAN_POINT('',(669.994479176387,-78.2543362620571,55.));
#658=DIRECTION('',(0.,0.,-1.));
#659=DIRECTION('',(-1.,0.,0.));
#660=AXIS2_PLACEMENT_3D('',#657,#658,#659);
#661=CYLINDRICAL_SURFACE('',#660,40.);
#662=DIRECTION('',(0.,0.,-1.));
#663=VECTOR('',#662,1.);
#664=CARTESIAN_POINT('',(633.984863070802,-95.6700632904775,55.));
#665=LINE('',#664,#663);
#666=CARTESIAN_POINT('',(633.984863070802,-95.6700632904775,30.));
#667=VERTEX_POINT('',#666);
#668=CARTESIAN_POINT('',(633.984863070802,-95.6700632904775,-30.));
#669=VERTEX_POINT('',#668);
#670=EDGE_CURVE('E514',#667,#669,#665,.T.);
#671=ORIENTED_EDGE('',*,*,#670,.T.);
#672=CARTESIAN_POINT('',(669.994479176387,-78.2543362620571,-30.));
#673=DIRECTION('',(0.,0.,1.));
#674=DIRECTION('',(1.,0.,0.));
#675=AXIS2_PLACEMENT_3D('',#672,#673,#674);
#676=CIRCLE('',#675,40.);
#677=EDGE_CURVE('E517',#669,#358,#676,.T.);
#678=ORIENTED_EDGE('',*,*,#677,.T.);
#679=ORIENTED_EDGE('',*,*,#374,.T.);
#680=ORIENTED_EDGE('',*,*,#622,.T.);
#681=DIRECTION('',(0.,0.,-1.));
#682=VECTOR('',#681,1.);
#683=CARTESIAN_POINT('',(633.544682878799,-61.7797391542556,55.));
#684=LINE('',#683,#682);
#685=EDGE_CURVE('E498',#459,#621,#684,.T.);
#686=ORIENTED_EDGE('',*,*,#685,.F.);
#687=ORIENTED_EDGE('',*,*,#460,.F.);
#688=CARTESIAN_POINT('',(658.968984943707,-116.70480409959,30.));
#689=VERTEX_POINT('',#688);
#690=EDGE_CURVE('E449',#457,#689,#373,.T.);
#691=ORIENTED_EDGE('',*,*,#690,.T.);
#692=CARTESIAN_POINT('',(669.994479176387,-78.2543362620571,30.));
#693=DIRECTION('',(0.,0.,1.));
#694=DIRECTION('',(1.,0.,0.));
#695=AXIS2_PLACEMENT_3D('',#692,#693,#694);
#696=CIRCLE('',#695,40.);
#697=EDGE_CURVE('E48',#689,#667,#696,.F.);
#698=ORIENTED_EDGE('',*,*,#697,.T.);
#699=EDGE_LOOP('',(#671,#678,#679,#680,#686,#687,#691,#698));
#700=FACE_BOUND('',#699,.T.);
#701=ADVANCED_FACE('F539',(#700),#661,.F.);
#702=CARTESIAN_POINT('',(496.857946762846,0.,55.));
#703=DIRECTION('',(0.,0.,-1.));
#704=DIRECTION('',(-1.,0.,0.));
#705=AXIS2_PLACEMENT_3D('',#702,#703,#704);
#706=CYLINDRICAL_SURFACE('',#705,150.);
#707=ORIENTED_EDGE('',*,*,#649,.T.);
#708=DIRECTION('',(0.,0.,-1.));
#709=VECTOR('',#708,1.);
#710=CARTESIAN_POINT('',(633.544682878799,61.7797391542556,55.));
#711=LINE('',#710,#709);
#712=EDGE_CURVE('E495',#468,#641,#711,.T.);
#713=ORIENTED_EDGE('',*,*,#712,.F.);
#714=ORIENTED_EDGE('',*,*,#469,.F.);
#715=ORIENTED_EDGE('',*,*,#685,.T.);
#716=EDGE_LOOP('',(#707,#713,#714,#715));
#717=FACE_BOUND('',#716,.T.);
#718=ADVANCED_FACE('F627',(#717),#706,.T.);
#719=CARTESIAN_POINT('',(669.994479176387,78.2543362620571,55.));
#720=DIRECTION('',(0.,0.,-1.));
#721=DIRECTION('',(-1.,0.,0.));
#722=AXIS2_PLACEMENT_3D('',#719,#720,#721);
#723=CYLINDRICAL_SURFACE('',#722,40.);
#724=DIRECTION('',(0.,0.,-1.));
#725=VECTOR('',#724,1.);
#726=CARTESIAN_POINT('',(633.984863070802,95.6700632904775,55.));
#727=LINE('',#726,#725);
#728=CARTESIAN_POINT('',(633.984863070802,95.6700632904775,-30.));
#729=VERTEX_POINT('',#728);
#730=CARTESIAN_POINT('',(633.984863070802,95.6700632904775,30.));
#731=VERTEX_POINT('',#730);
#732=EDGE_CURVE('E506',#729,#731,#727,.F.);
#733=ORIENTED_EDGE('',*,*,#732,.T.);
#734=CARTESIAN_POINT('',(669.994479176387,78.2543362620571,30.));
#735=DIRECTION('',(0.,0.,1.));
#736=DIRECTION('',(1.,0.,0.));
#737=AXIS2_PLACEMENT_3D('',#734,#735,#736);
#738=CIRCLE('',#737,40.);
#739=CARTESIAN_POINT('',(658.968984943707,116.70480409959,30.));
#740=VERTEX_POINT('',#739);
#741=EDGE_CURVE('E509',#731,#740,#738,.F.);
#742=ORIENTED_EDGE('',*,*,#741,.T.);
#743=EDGE_CURVE('E492',#477,#740,#37,.T.);
#744=ORIENTED_EDGE('',*,*,#743,.F.);
#745=ORIENTED_EDGE('',*,*,#478,.F.);
#746=ORIENTED_EDGE('',*,*,#712,.T.);
#747=ORIENTED_EDGE('',*,*,#642,.T.);
#748=ORIENTED_EDGE('',*,*,#40,.F.);
#749=CARTESIAN_POINT('',(669.994479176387,78.2543362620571,-30.));
#750=DIRECTION('',(0.,0.,1.));
#751=DIRECTION('',(1.,0.,0.));
#752=AXIS2_PLACEMENT_3D('',#749,#750,#751);
#753=CIRCLE('',#752,40.);
#754=EDGE_CURVE('E56',#29,#729,#753,.T.);
#755=ORIENTED_EDGE('',*,*,#754,.T.);
#756=EDGE_LOOP('',(#733,#742,#744,#745,#746,#747,#748,#755));
#757=FACE_BOUND('',#756,.T.);
#758=ADVANCED_FACE('F593',(#757),#723,.F.);
#759=ORIENTED_EDGE('',*,*,#743,.T.);
#760=DIRECTION('',(0.961261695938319,0.275637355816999,0.));
#761=VECTOR('',#760,1.);
#762=CARTESIAN_POINT('',(849.712684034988,171.399679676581,30.));
#763=LINE('',#762,#761);
#764=CARTESIAN_POINT('',(737.793083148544,139.307250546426,30.));
#765=VERTEX_POINT('',#764);
#766=EDGE_CURVE('E298',#740,#765,#763,.T.);
#767=ORIENTED_EDGE('',*,*,#766,.T.);
#768=EDGE_CURVE('E488',#485,#765,#53,.T.);
#769=ORIENTED_EDGE('',*,*,#768,.F.);
#770=ORIENTED_EDGE('',*,*,#486,.F.);
#771=EDGE_LOOP('',(#759,#767,#769,#770));
#772=FACE_BOUND('',#771,.T.);
#773=ADVANCED_FACE('F587',(#772),#23,.F.);
#774=ORIENTED_EDGE('',*,*,#768,.T.);
#775=CARTESIAN_POINT('',(732.280336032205,158.532484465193,30.));
#776=DIRECTION('',(0.,0.,1.));
#777=DIRECTION('',(1.,0.,0.));
#778=AXIS2_PLACEMENT_3D('',#775,#776,#777);
#779=CIRCLE('',#778,20.);
#780=CARTESIAN_POINT('',(751.505569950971,164.045231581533,30.));
#781=VERTEX_POINT('',#780);
#782=EDGE_CURVE('E338',#765,#781,#779,.T.);
#783=ORIENTED_EDGE('',*,*,#782,.T.);
#784=EDGE_CURVE('E484',#494,#781,#86,.T.);
#785=ORIENTED_EDGE('',*,*,#784,.F.);
#786=ORIENTED_EDGE('',*,*,#495,.F.);
#787=EDGE_LOOP('',(#774,#783,#785,#786));
#788=FACE_BOUND('',#787,.T.);
#789=ADVANCED_FACE('F582',(#788),#63,.T.);
#790=ORIENTED_EDGE('',*,*,#784,.T.);
#791=DIRECTION('',(-0.275637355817,0.961261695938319,0.));
#792=VECTOR('',#791,1.);
#793=CARTESIAN_POINT('',(751.505569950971,164.045231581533,30.));
#794=LINE('',#793,#792);
#795=CARTESIAN_POINT('',(734.967328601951,221.720933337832,30.));
#796=VERTEX_POINT('',#795);
#797=EDGE_CURVE('E335',#781,#796,#794,.T.);
#798=ORIENTED_EDGE('',*,*,#797,.T.);
#799=EDGE_CURVE('E480',#502,#796,#117,.T.);
#800=ORIENTED_EDGE('',*,*,#799,.F.);
#801=ORIENTED_EDGE('',*,*,#503,.F.);
#802=EDGE_LOOP('',(#790,#798,#800,#801));
#803=FACE_BOUND('',#802,.T.);
#804=ADVANCED_FACE('F578',(#803),#96,.F.);
#805=ORIENTED_EDGE('',*,*,#799,.T.);
#806=CARTESIAN_POINT('',(715.742094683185,216.208186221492,30.));
#807=DIRECTION('',(0.,0.,1.));
#808=DIRECTION('',(1.,0.,0.));
#809=AXIS2_PLACEMENT_3D('',#806,#807,#808);
#810=CIRCLE('',#809,20.);
#811=CARTESIAN_POINT('',(710.229347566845,235.433420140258,30.));
#812=VERTEX_POINT('',#811);
#813=EDGE_CURVE('E332',#796,#812,#810,.T.);
#814=ORIENTED_EDGE('',*,*,#813,.T.);
#815=EDGE_CURVE('E476',#511,#812,#150,.T.);
#816=ORIENTED_EDGE('',*,*,#815,.F.);
#817=ORIENTED_EDGE('',*,*,#512,.F.);
#818=EDGE_LOOP('',(#805,#814,#816,#817));
#819=FACE_BOUND('',#818,.T.);
#820=ADVANCED_FACE('F573',(#819),#127,.T.);
#821=ORIENTED_EDGE('',*,*,#815,.T.);
#822=DIRECTION('',(-0.961261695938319,-0.275637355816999,0.));
#823=VECTOR('',#822,1.);
#824=CARTESIAN_POINT('',(464.549050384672,164.985728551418,30.));
#825=LINE('',#824,#823);
#826=CARTESIAN_POINT('',(464.549050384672,164.985728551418,30.));
#827=VERTEX_POINT('',#826);
#828=EDGE_CURVE('E329',#812,#827,#825,.T.);
#829=ORIENTED_EDGE('',*,*,#828,.T.);
#830=EDGE_CURVE('E472',#519,#827,#181,.T.);
#831=ORIENTED_EDGE('',*,*,#830,.F.);
#832=ORIENTED_EDGE('',*,*,#520,.F.);
#833=EDGE_LOOP('',(#821,#829,#831,#832));
#834=FACE_BOUND('',#833,.T.);
#835=ADVANCED_FACE('F570',(#834),#160,.F.);
#836=ORIENTED_EDGE('',*,*,#830,.T.);
#837=CARTESIAN_POINT('',(511.857946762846,0.,30.));
#838=DIRECTION('',(0.,0.,1.));
#839=DIRECTION('',(1.,0.,0.));
#840=AXIS2_PLACEMENT_3D('',#837,#838,#839);
#841=CIRCLE('',#840,171.634560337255);
#842=CARTESIAN_POINT('',(464.549050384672,-164.985728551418,30.));
#843=VERTEX_POINT('',#842);
#844=EDGE_CURVE('E326',#827,#843,#841,.T.);
#845=ORIENTED_EDGE('',*,*,#844,.T.);
#846=EDGE_CURVE('E468',#528,#843,#214,.T.);
#847=ORIENTED_EDGE('',*,*,#846,.F.);
#848=ORIENTED_EDGE('',*,*,#529,.F.);
#849=EDGE_LOOP('',(#836,#845,#847,#848));
#850=FACE_BOUND('',#849,.T.);
#851=ADVANCED_FACE('F565',(#850),#191,.T.);
#852=ORIENTED_EDGE('',*,*,#846,.T.);
#853=DIRECTION('',(0.961261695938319,-0.275637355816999,0.));
#854=VECTOR('',#853,1.);
#855=CARTESIAN_POINT('',(464.549050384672,-164.985728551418,30.));
#856=LINE('',#855,#854);
#857=CARTESIAN_POINT('',(710.229347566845,-235.433420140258,30.));
#858=VERTEX_POINT('',#857);
#859=EDGE_CURVE('E323',#843,#858,#856,.T.);
#860=ORIENTED_EDGE('',*,*,#859,.T.);
#861=EDGE_CURVE('E464',#536,#858,#245,.T.);
#862=ORIENTED_EDGE('',*,*,#861,.F.);
#863=ORIENTED_EDGE('',*,*,#537,.F.);
#864=EDGE_LOOP('',(#852,#860,#862,#863));
#865=FACE_BOUND('',#864,.T.);
#866=ADVANCED_FACE('F562',(#865),#224,.F.);
#867=ORIENTED_EDGE('',*,*,#861,.T.);
#868=CARTESIAN_POINT('',(715.742094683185,-216.208186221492,30.));
#869=DIRECTION('',(0.,0.,1.));
#870=DIRECTION('',(1.,0.,0.));
#871=AXIS2_PLACEMENT_3D('',#868,#869,#870);
#872=CIRCLE('',#871,20.);
#873=CARTESIAN_POINT('',(734.967328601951,-221.720933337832,30.));
#874=VERTEX_POINT('',#873);
#875=EDGE_CURVE('E320',#858,#874,#872,.T.);
#876=ORIENTED_EDGE('',*,*,#875,.T.);
#877=EDGE_CURVE('E460',#545,#874,#278,.T.);
#878=ORIENTED_EDGE('',*,*,#877,.F.);
#879=ORIENTED_EDGE('',*,*,#546,.F.);
#880=EDGE_LOOP('',(#867,#876,#878,#879));
#881=FACE_BOUND('',#880,.T.);
#882=ADVANCED_FACE('F557',(#881),#255,.T.);
#883=ORIENTED_EDGE('',*,*,#877,.T.);
#884=DIRECTION('',(0.275637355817,0.961261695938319,0.));
#885=VECTOR('',#884,1.);
#886=CARTESIAN_POINT('',(751.505569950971,-164.045231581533,30.));
#887=LINE('',#886,#885);
#888=CARTESIAN_POINT('',(751.505569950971,-164.045231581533,30.));
#889=VERTEX_POINT('',#888);
#890=EDGE_CURVE('E317',#874,#889,#887,.T.);
#891=ORIENTED_EDGE('',*,*,#890,.T.);
#892=EDGE_CURVE('E456',#553,#889,#309,.T.);
#893=ORIENTED_EDGE('',*,*,#892,.F.);
#894=ORIENTED_EDGE('',*,*,#554,.F.);
#895=EDGE_LOOP('',(#883,#891,#893,#894));
#896=FACE_BOUND('',#895,.T.);
#897=ADVANCED_FACE('F554',(#896),#288,.F.);
#898=ORIENTED_EDGE('',*,*,#892,.T.);
#899=CARTESIAN_POINT('',(732.280336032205,-158.532484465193,30.));
#900=DIRECTION('',(0.,0.,1.));
#901=DIRECTION('',(1.,0.,0.));
#902=AXIS2_PLACEMENT_3D('',#899,#900,#901);
#903=CIRCLE('',#902,20.);
#904=CARTESIAN_POINT('',(737.793083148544,-139.307250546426,30.));
#905=VERTEX_POINT('',#904);
#906=EDGE_CURVE('E314',#889,#905,#903,.T.);
#907=ORIENTED_EDGE('',*,*,#906,.T.);
#908=EDGE_CURVE('E452',#562,#905,#342,.T.);
#909=ORIENTED_EDGE('',*,*,#908,.F.);
#910=ORIENTED_EDGE('',*,*,#563,.F.);
#911=EDGE_LOOP('',(#898,#907,#909,#910));
#912=FACE_BOUND('',#911,.T.);
#913=ADVANCED_FACE('F549',(#912),#319,.T.);
#914=ORIENTED_EDGE('',*,*,#908,.T.);
#915=DIRECTION('',(-0.961261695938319,0.275637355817,0.));
#916=VECTOR('',#915,1.);
#917=CARTESIAN_POINT('',(860.229370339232,-174.415290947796,30.));
#918=LINE('',#917,#916);
#919=EDGE_CURVE('E291',#905,#689,#918,.T.);
#920=ORIENTED_EDGE('',*,*,#919,.T.);
#921=ORIENTED_EDGE('',*,*,#690,.F.);
#922=ORIENTED_EDGE('',*,*,#569,.F.);
#923=EDGE_LOOP('',(#914,#920,#921,#922));
#924=FACE_BOUND('',#923,.T.);
#925=ADVANCED_FACE('F546',(#924),#352,.F.);
#926=CARTESIAN_POINT('',(496.857946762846,0.,55.));
#927=DIRECTION('',(0.,0.,-1.));
#928=DIRECTION('',(-1.,0.,0.));
#929=AXIS2_PLACEMENT_3D('',#926,#927,#928);
#930=CYLINDRICAL_SURFACE('',#929,117.5);
#931=CARTESIAN_POINT('',(496.857946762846,0.,30.));
#932=DIRECTION('',(0.,0.,1.));
#933=DIRECTION('',(1.,0.,0.));
#934=AXIS2_PLACEMENT_3D('',#931,#932,#933);
#935=CIRCLE('',#934,117.5);
#936=CARTESIAN_POINT('',(614.357946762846,0.,30.));
#937=VERTEX_POINT('',#936);
#938=EDGE_CURVE('E311',#937,#937,#935,.T.);
#939=ORIENTED_EDGE('',*,*,#938,.F.);
#940=EDGE_LOOP('',(#939));
#941=FACE_BOUND('',#940,.T.);
#942=ORIENTED_EDGE('',*,*,#580,.T.);
#943=EDGE_LOOP('',(#942));
#944=FACE_BOUND('',#943,.T.);
#945=ADVANCED_FACE('F654',(#941,#944),#930,.F.);
#946=CARTESIAN_POINT('',(704.785981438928,181.857588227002,30.));
#947=DIRECTION('',(0.,0.,1.));
#948=DIRECTION('',(1.,0.,0.));
#949=AXIS2_PLACEMENT_3D('',#946,#947,#948);
#950=CIRCLE('',#949,19.);
#951=CARTESIAN_POINT('',(723.785981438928,181.857588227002,30.));
#952=VERTEX_POINT('',#951);
#953=EDGE_CURVE('E308',#952,#952,#950,.T.);
#954=ORIENTED_EDGE('',*,*,#953,.F.);
#955=EDGE_LOOP('',(#954));
#956=FACE_BOUND('',#955,.T.);
#957=ORIENTED_EDGE('',*,*,#447,.T.);
#958=EDGE_LOOP('',(#957));
#959=FACE_BOUND('',#958,.T.);
#960=ADVANCED_FACE('F741',(#956,#959),#383,.F.);
#961=CARTESIAN_POINT('',(704.785981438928,-181.857588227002,30.));
#962=DIRECTION('',(0.,0.,1.));
#963=DIRECTION('',(1.,0.,0.));
#964=AXIS2_PLACEMENT_3D('',#961,#962,#963);
#965=CIRCLE('',#964,19.);
#966=CARTESIAN_POINT('',(723.785981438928,-181.857588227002,30.));
#967=VERTEX_POINT('',#966);
#968=EDGE_CURVE('E303',#967,#967,#965,.T.);
#969=ORIENTED_EDGE('',*,*,#968,.F.);
#970=EDGE_LOOP('',(#969));
#971=FACE_BOUND('',#970,.T.);
#972=ORIENTED_EDGE('',*,*,#591,.T.);
#973=EDGE_LOOP('',(#972));
#974=FACE_BOUND('',#973,.T.);
#975=ADVANCED_FACE('F739',(#971,#974),#411,.F.);
#976=CARTESIAN_POINT('',(849.712684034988,171.399679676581,-30.));
#977=DIRECTION('',(0.275637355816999,-0.961261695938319,0.));
#978=DIRECTION('',(0.961261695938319,0.275637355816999,0.));
#979=AXIS2_PLACEMENT_3D('',#976,#977,#978);
#980=PLANE('',#979);
#981=CARTESIAN_POINT('',(620.079250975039,105.553352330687,30.));
#982=VERTEX_POINT('',#981);
#983=CARTESIAN_POINT('',(624.57784100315,106.843302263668,30.));
#984=VERTEX_POINT('',#983);
#985=EDGE_CURVE('E299',#982,#984,#763,.T.);
#986=ORIENTED_EDGE('',*,*,#985,.T.);
#987=DIRECTION('',(0.,0.,-1.));
#988=VECTOR('',#987,1.);
#989=CARTESIAN_POINT('',(624.57784100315,106.843302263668,-30.));
#990=LINE('',#989,#988);
#991=CARTESIAN_POINT('',(624.57784100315,106.843302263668,-30.));
#992=VERTEX_POINT('',#991);
#993=EDGE_CURVE('E511',#984,#992,#990,.T.);
#994=ORIENTED_EDGE('',*,*,#993,.T.);
#995=CARTESIAN_POINT('',(620.079250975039,105.553352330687,-30.));
#996=VERTEX_POINT('',#995);
#997=EDGE_CURVE('E282',#996,#992,#27,.T.);
#998=ORIENTED_EDGE('',*,*,#997,.F.);
#999=DIRECTION('',(0.,0.,1.));
#1000=VECTOR('',#999,1.);
#1001=CARTESIAN_POINT('',(620.079250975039,105.553352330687,-30.));
#1002=LINE('',#1001,#1000);
#1003=EDGE_CURVE('E276',#996,#982,#1002,.T.);
#1004=ORIENTED_EDGE('',*,*,#1003,.T.);
#1005=EDGE_LOOP('',(#986,#994,#998,#1004));
#1006=FACE_BOUND('',#1005,.T.);
#1007=ADVANCED_FACE('F599',(#1006),#980,.F.);
#1008=CARTESIAN_POINT('',(860.229370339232,-174.415290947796,-30.));
#1009=DIRECTION('',(0.275637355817,0.961261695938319,0.));
#1010=DIRECTION('',(-0.961261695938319,0.275637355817,0.));
#1011=AXIS2_PLACEMENT_3D('',#1008,#1009,#1010);
#1012=PLANE('',#1011);
#1013=CARTESIAN_POINT('',(624.57784100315,-106.843302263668,-30.));
#1014=VERTEX_POINT('',#1013);
#1015=CARTESIAN_POINT('',(620.079250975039,-105.553352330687,-30.));
#1016=VERTEX_POINT('',#1015);
#1017=EDGE_CURVE('E302',#1014,#1016,#356,.T.);
#1018=ORIENTED_EDGE('',*,*,#1017,.F.);
#1019=DIRECTION('',(0.,0.,-1.));
#1020=VECTOR('',#1019,1.);
#1021=CARTESIAN_POINT('',(624.57784100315,-106.843302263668,-30.));
#1022=LINE('',#1021,#1020);
#1023=CARTESIAN_POINT('',(624.57784100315,-106.843302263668,30.));
#1024=VERTEX_POINT('',#1023);
#1025=EDGE_CURVE('E519',#1014,#1024,#1022,.F.);
#1026=ORIENTED_EDGE('',*,*,#1025,.T.);
#1027=CARTESIAN_POINT('',(620.079250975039,-105.553352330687,30.));
#1028=VERTEX_POINT('',#1027);
#1029=EDGE_CURVE('E289',#1024,#1028,#918,.T.);
#1030=ORIENTED_EDGE('',*,*,#1029,.T.);
#1031=DIRECTION('',(0.,0.,1.));
#1032=VECTOR('',#1031,1.);
#1033=CARTESIAN_POINT('',(620.079250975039,-105.553352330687,-30.));
#1034=LINE('',#1033,#1032);
#1035=EDGE_CURVE('E288',#1016,#1028,#1034,.T.);
#1036=ORIENTED_EDGE('',*,*,#1035,.F.);
#1037=EDGE_LOOP('',(#1018,#1026,#1030,#1036));
#1038=FACE_BOUND('',#1037,.T.);
#1039=ADVANCED_FACE('F532',(#1038),#1012,.F.);
#1040=CARTESIAN_POINT('',(625.591998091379,-86.3281184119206,-30.));
#1041=DIRECTION('',(0.,0.,1.));
#1042=DIRECTION('',(1.,0.,0.));
#1043=AXIS2_PLACEMENT_3D('',#1040,#1041,#1042);
#1044=PLANE('',#1043);
#1045=CARTESIAN_POINT('',(496.857946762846,0.,-30.));
#1046=DIRECTION('',(0.,0.,1.));
#1047=DIRECTION('',(1.,0.,0.));
#1048=AXIS2_PLACEMENT_3D('',#1045,#1046,#1047);
#1049=CIRCLE('',#1048,135.);
#1050=CARTESIAN_POINT('',(608.981152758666,75.1890063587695,-30.));
#1051=VERTEX_POINT('',#1050);
#1052=CARTESIAN_POINT('',(608.981152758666,-75.1890063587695,-30.));
#1053=VERTEX_POINT('',#1052);
#1054=EDGE_CURVE('E253',#1051,#1053,#1049,.T.);
#1055=ORIENTED_EDGE('',*,*,#1054,.F.);
#1056=CARTESIAN_POINT('',(625.591998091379,86.3281184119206,-30.));
#1057=DIRECTION('',(0.,0.,-1.));
#1058=DIRECTION('',(1.,0.,0.));
#1059=AXIS2_PLACEMENT_3D('',#1056,#1057,#1058);
#1060=CIRCLE('',#1059,20.);
#1061=EDGE_CURVE('E259',#1051,#996,#1060,.T.);
#1062=ORIENTED_EDGE('',*,*,#1061,.T.);
#1063=ORIENTED_EDGE('',*,*,#997,.T.);
#1064=CARTESIAN_POINT('',(626.782939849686,99.1532086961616,-30.));
#1065=DIRECTION('',(0.,0.,1.));
#1066=DIRECTION('',(1.,0.,0.));
#1067=AXIS2_PLACEMENT_3D('',#1064,#1065,#1066);
#1068=CIRCLE('',#1067,8.);
#1069=EDGE_CURVE('E523',#992,#729,#1068,.F.);
#1070=ORIENTED_EDGE('',*,*,#1069,.T.);
#1071=ORIENTED_EDGE('',*,*,#754,.F.);
#1072=ORIENTED_EDGE('',*,*,#32,.T.);
#1073=ORIENTED_EDGE('',*,*,#71,.T.);
#1074=ORIENTED_EDGE('',*,*,#103,.T.);
#1075=ORIENTED_EDGE('',*,*,#135,.T.);
#1076=ORIENTED_EDGE('',*,*,#167,.T.);
#1077=ORIENTED_EDGE('',*,*,#199,.T.);
#1078=ORIENTED_EDGE('',*,*,#231,.T.);
#1079=ORIENTED_EDGE('',*,*,#263,.T.);
#1080=ORIENTED_EDGE('',*,*,#295,.T.);
#1081=ORIENTED_EDGE('',*,*,#327,.T.);
#1082=ORIENTED_EDGE('',*,*,#359,.T.);
#1083=ORIENTED_EDGE('',*,*,#677,.F.);
#1084=CARTESIAN_POINT('',(626.782939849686,-99.1532086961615,-30.));
#1085=DIRECTION('',(0.,0.,1.));
#1086=DIRECTION('',(1.,0.,0.));
#1087=AXIS2_PLACEMENT_3D('',#1084,#1085,#1086);
#1088=CIRCLE('',#1087,8.);
#1089=EDGE_CURVE('E42',#669,#1014,#1088,.F.);
#1090=ORIENTED_EDGE('',*,*,#1089,.T.);
#1091=ORIENTED_EDGE('',*,*,#1017,.T.);
#1092=CARTESIAN_POINT('',(625.591998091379,-86.3281184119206,-30.));
#1093=DIRECTION('',(0.,0.,-1.));
#1094=DIRECTION('',(1.,0.,0.));
#1095=AXIS2_PLACEMENT_3D('',#1092,#1093,#1094);
#1096=CIRCLE('',#1095,20.);
#1097=EDGE_CURVE('E262',#1016,#1053,#1096,.T.);
#1098=ORIENTED_EDGE('',*,*,#1097,.T.);
#1099=EDGE_LOOP('',(#1055,#1062,#1063,#1070,#1071,#1072,#1073,#1074,#1075,#1076,#1077,#1078,
#1079,#1080,#1081,#1082,#1083,#1090,#1091,#1098));
#1100=FACE_BOUND('',#1099,.T.);
#1101=ORIENTED_EDGE('',*,*,#430,.F.);
#1102=EDGE_LOOP('',(#1101));
#1103=FACE_BOUND('',#1102,.T.);
#1104=ORIENTED_EDGE('',*,*,#402,.F.);
#1105=EDGE_LOOP('',(#1104));
#1106=FACE_BOUND('',#1105,.T.);
#1107=ADVANCED_FACE('F255',(#1100,#1103,#1106),#1044,.T.);
#1108=CARTESIAN_POINT('',(625.591998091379,-86.3281184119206,30.));
#1109=DIRECTION('',(0.,0.,1.));
#1110=DIRECTION('',(1.,0.,0.));
#1111=AXIS2_PLACEMENT_3D('',#1108,#1109,#1110);
#1112=PLANE('',#1111);
#1113=ORIENTED_EDGE('',*,*,#968,.T.);
#1114=EDGE_LOOP('',(#1113));
#1115=FACE_BOUND('',#1114,.T.);
#1116=ORIENTED_EDGE('',*,*,#953,.T.);
#1117=EDGE_LOOP('',(#1116));
#1118=FACE_BOUND('',#1117,.T.);
#1119=ORIENTED_EDGE('',*,*,#938,.T.);
#1120=EDGE_LOOP('',(#1119));
#1121=FACE_BOUND('',#1120,.T.);
#1122=ORIENTED_EDGE('',*,*,#766,.F.);
#1123=ORIENTED_EDGE('',*,*,#741,.F.);
#1124=CARTESIAN_POINT('',(626.782939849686,99.1532086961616,30.));
#1125=DIRECTION('',(0.,0.,1.));
#1126=DIRECTION('',(1.,0.,0.));
#1127=AXIS2_PLACEMENT_3D('',#1124,#1125,#1126);
#1128=CIRCLE('',#1127,8.);
#1129=EDGE_CURVE('E521',#731,#984,#1128,.T.);
#1130=ORIENTED_EDGE('',*,*,#1129,.T.);
#1131=ORIENTED_EDGE('',*,*,#985,.F.);
#1132=CARTESIAN_POINT('',(625.591998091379,86.3281184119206,30.));
#1133=DIRECTION('',(0.,0.,-1.));
#1134=DIRECTION('',(1.,0.,0.));
#1135=AXIS2_PLACEMENT_3D('',#1132,#1133,#1134);
#1136=CIRCLE('',#1135,20.);
#1137=CARTESIAN_POINT('',(608.981152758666,75.1890063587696,30.));
#1138=VERTEX_POINT('',#1137);
#1139=EDGE_CURVE('E296',#1138,#982,#1136,.T.);
#1140=ORIENTED_EDGE('',*,*,#1139,.F.);
#1141=CARTESIAN_POINT('',(496.857946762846,0.,30.));
#1142=DIRECTION('',(0.,0.,1.));
#1143=DIRECTION('',(1.,0.,0.));
#1144=AXIS2_PLACEMENT_3D('',#1141,#1142,#1143);
#1145=CIRCLE('',#1144,135.);
#1146=CARTESIAN_POINT('',(608.981152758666,-75.1890063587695,30.));
#1147=VERTEX_POINT('',#1146);
#1148=EDGE_CURVE('E272',#1147,#1138,#1145,.T.);
#1149=ORIENTED_EDGE('',*,*,#1148,.F.);
#1150=CARTESIAN_POINT('',(625.591998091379,-86.3281184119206,30.));
#1151=DIRECTION('',(0.,0.,-1.));
#1152=DIRECTION('',(1.,0.,0.));
#1153=AXIS2_PLACEMENT_3D('',#1150,#1151,#1152);
#1154=CIRCLE('',#1153,20.);
#1155=EDGE_CURVE('E292',#1028,#1147,#1154,.T.);
#1156=ORIENTED_EDGE('',*,*,#1155,.F.);
#1157=ORIENTED_EDGE('',*,*,#1029,.F.);
#1158=CARTESIAN_POINT('',(626.782939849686,-99.1532086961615,30.));
#1159=DIRECTION('',(0.,0.,1.));
#1160=DIRECTION('',(1.,0.,0.));
#1161=AXIS2_PLACEMENT_3D('',#1158,#1159,#1160);
#1162=CIRCLE('',#1161,8.);
#1163=EDGE_CURVE('E11',#1024,#667,#1162,.T.);
#1164=ORIENTED_EDGE('',*,*,#1163,.T.);
#1165=ORIENTED_EDGE('',*,*,#697,.F.);
#1166=ORIENTED_EDGE('',*,*,#919,.F.);
#1167=ORIENTED_EDGE('',*,*,#906,.F.);
#1168=ORIENTED_EDGE('',*,*,#890,.F.);
#1169=ORIENTED_EDGE('',*,*,#875,.F.);
#1170=ORIENTED_EDGE('',*,*,#859,.F.);
#1171=ORIENTED_EDGE('',*,*,#844,.F.);
#1172=ORIENTED_EDGE('',*,*,#828,.F.);
#1173=ORIENTED_EDGE('',*,*,#813,.F.);
#1174=ORIENTED_EDGE('',*,*,#797,.F.);
#1175=ORIENTED_EDGE('',*,*,#782,.F.);
#1176=EDGE_LOOP('',(#1122,#1123,#1130,#1131,#1140,#1149,#1156,#1157,#1164,#1165,#1166,#1167,
#1168,#1169,#1170,#1171,#1172,#1173,#1174,#1175));
#1177=FACE_BOUND('',#1176,.T.);
#1178=ADVANCED_FACE('F536',(#1115,#1118,#1121,#1177),#1112,.F.);
#1179=CARTESIAN_POINT('',(625.591998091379,86.3281184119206,-30.));
#1180=DIRECTION('',(0.,0.,1.));
#1181=DIRECTION('',(1.,0.,0.));
#1182=AXIS2_PLACEMENT_3D('',#1179,#1180,#1181);
#1183=CYLINDRICAL_SURFACE('',#1182,20.);
#1184=ORIENTED_EDGE('',*,*,#1139,.T.);
#1185=ORIENTED_EDGE('',*,*,#1003,.F.);
#1186=ORIENTED_EDGE('',*,*,#1061,.F.);
#1187=DIRECTION('',(0.,0.,1.));
#1188=VECTOR('',#1187,1.);
#1189=CARTESIAN_POINT('',(608.981152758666,75.1890063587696,-30.));
#1190=LINE('',#1189,#1188);
#1191=EDGE_CURVE('E268',#1051,#1138,#1190,.T.);
#1192=ORIENTED_EDGE('',*,*,#1191,.T.);
#1193=EDGE_LOOP('',(#1184,#1185,#1186,#1192));
#1194=FACE_BOUND('',#1193,.T.);
#1195=ADVANCED_FACE('F279',(#1194),#1183,.T.);
#1196=CARTESIAN_POINT('',(496.857946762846,0.,-30.));
#1197=DIRECTION('',(0.,0.,1.));
#1198=DIRECTION('',(1.,0.,0.));
#1199=AXIS2_PLACEMENT_3D('',#1196,#1197,#1198);
#1200=CYLINDRICAL_SURFACE('',#1199,135.);
#1201=ORIENTED_EDGE('',*,*,#1148,.T.);
#1202=ORIENTED_EDGE('',*,*,#1191,.F.);
#1203=ORIENTED_EDGE('',*,*,#1054,.T.);
#1204=DIRECTION('',(0.,0.,1.));
#1205=VECTOR('',#1204,1.);
#1206=CARTESIAN_POINT('',(608.981152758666,-75.1890063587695,-30.));
#1207=LINE('',#1206,#1205);
#1208=EDGE_CURVE('E277',#1053,#1147,#1207,.T.);
#1209=ORIENTED_EDGE('',*,*,#1208,.T.);
#1210=EDGE_LOOP('',(#1201,#1202,#1203,#1209));
#1211=FACE_BOUND('',#1210,.T.);
#1212=ORIENTED_EDGE('',*,*,#608,.F.);
#1213=EDGE_LOOP('',(#1212));
#1214=FACE_BOUND('',#1213,.T.);
#1215=ADVANCED_FACE('F269',(#1211,#1214),#1200,.F.);
#1216=CARTESIAN_POINT('',(625.591998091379,-86.3281184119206,-30.));
#1217=DIRECTION('',(0.,0.,1.));
#1218=DIRECTION('',(1.,0.,0.));
#1219=AXIS2_PLACEMENT_3D('',#1216,#1217,#1218);
#1220=CYLINDRICAL_SURFACE('',#1219,20.);
#1221=ORIENTED_EDGE('',*,*,#1155,.T.);
#1222=ORIENTED_EDGE('',*,*,#1208,.F.);
#1223=ORIENTED_EDGE('',*,*,#1097,.F.);
#1224=ORIENTED_EDGE('',*,*,#1035,.T.);
#1225=EDGE_LOOP('',(#1221,#1222,#1223,#1224));
#1226=FACE_BOUND('',#1225,.T.);
#1227=ADVANCED_FACE('F601',(#1226),#1220,.T.);
#1228=CARTESIAN_POINT('',(626.782939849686,99.1532086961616,55.));
#1229=DIRECTION('',(0.,0.,-1.));
#1230=DIRECTION('',(-1.,0.,0.));
#1231=AXIS2_PLACEMENT_3D('',#1228,#1229,#1230);
#1232=CYLINDRICAL_SURFACE('',#1231,8.);
#1233=ORIENTED_EDGE('',*,*,#1069,.F.);
#1234=ORIENTED_EDGE('',*,*,#993,.F.);
#1235=ORIENTED_EDGE('',*,*,#1129,.F.);
#1236=ORIENTED_EDGE('',*,*,#732,.F.);
#1237=EDGE_LOOP('',(#1233,#1234,#1235,#1236));
#1238=FACE_BOUND('',#1237,.T.);
#1239=ADVANCED_FACE('F596',(#1238),#1232,.T.);
#1240=CARTESIAN_POINT('',(626.782939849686,-99.1532086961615,55.));
#1241=DIRECTION('',(0.,0.,-1.));
#1242=DIRECTION('',(-1.,0.,0.));
#1243=AXIS2_PLACEMENT_3D('',#1240,#1241,#1242);
#1244=CYLINDRICAL_SURFACE('',#1243,8.);
#1245=ORIENTED_EDGE('',*,*,#1163,.F.);
#1246=ORIENTED_EDGE('',*,*,#1025,.F.);
#1247=ORIENTED_EDGE('',*,*,#1089,.F.);
#1248=ORIENTED_EDGE('',*,*,#670,.F.);
#1249=EDGE_LOOP('',(#1245,#1246,#1247,#1248));
#1250=FACE_BOUND('',#1249,.T.);
#1251=ADVANCED_FACE('F36',(#1250),#1244,.T.);
#1252=CLOSED_SHELL('',(#58,#91,#122,#155,#186,#219,#250,#283,#314,#347,#378,#406,#434,#595,#656,
#701,#718,#758,#773,#789,#804,#820,#835,#851,#866,#882,#897,#913,#925,#945,#960,#975,#1007,
#1039,#1107,#1178,#1195,#1215,#1227,#1239,#1251));
#1253=MANIFOLD_SOLID_BREP('B2',#1252);
#1254=ADVANCED_BREP_SHAPE_REPRESENTATION('',(#18,#1253),#14);
#1255=SHAPE_DEFINITION_REPRESENTATION(#9,#1254);
ENDSEC;
END-ISO-10303-21;
